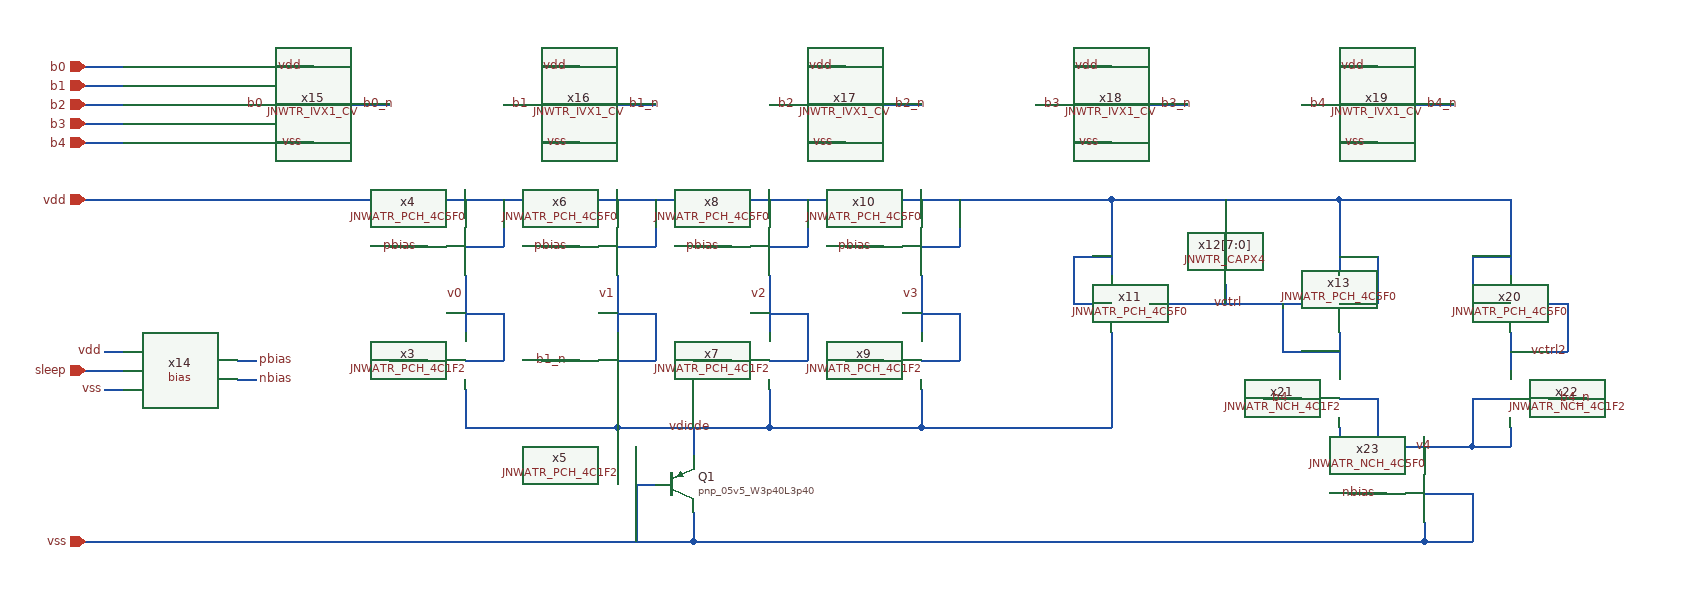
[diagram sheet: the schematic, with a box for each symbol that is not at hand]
v {xschem version=3.4.6 file_version=1.2}
G {}
K {}
V {}
S {}
E {}
N 830 540 830 570 {lab=vdiode}
N 510 350 550 350 {lab=pbias}
N 590 300 590 320 {lab=vdd}
N 590 380 590 440 {lab=v0}
N 590 500 590 540 {lab=vdiode}
N 510 470 550 470 {lab=b0_n}
N 590 350 630 350 {lab=vdd}
N 630 300 630 350 {lab=vdd}
N 590 470 630 470 {lab=v0}
N 630 420 630 470 {lab=v0}
N 590 420 630 420 {lab=v0}
N 590 540 750 540 {lab=vdiode}
N 670 350 710 350 {lab=pbias}
N 750 300 750 320 {lab=vdd}
N 750 380 750 440 {lab=v1}
N 750 500 750 540 {lab=vdiode}
N 670 470 710 470 {lab=b1_n}
N 750 350 790 350 {lab=vdd}
N 790 300 790 350 {lab=vdd}
N 750 470 790 470 {lab=v1}
N 790 420 790 470 {lab=v1}
N 750 420 790 420 {lab=v1}
N 750 540 910 540 {lab=vdiode}
N 830 350 870 350 {lab=pbias}
N 910 300 910 320 {lab=vdd}
N 910 380 910 440 {lab=v2}
N 910 500 910 540 {lab=vdiode}
N 830 470 870 470 {lab=b2_n}
N 910 350 950 350 {lab=vdd}
N 950 300 950 350 {lab=vdd}
N 910 470 950 470 {lab=v2}
N 950 420 950 470 {lab=v2}
N 910 420 950 420 {lab=v2}
N 910 540 1070 540 {lab=vdiode}
N 990 350 1030 350 {lab=pbias}
N 1070 300 1070 320 {lab=vdd}
N 1070 380 1070 440 {lab=v3}
N 1070 500 1070 540 {lab=vdiode}
N 990 470 1030 470 {lab=b3_n}
N 1070 350 1110 350 {lab=vdd}
N 1110 300 1110 350 {lab=vdd}
N 1070 470 1110 470 {lab=v3}
N 1110 420 1110 470 {lab=v3}
N 1070 420 1110 420 {lab=v3}
N 190 300 1270 300 {lab=vdd}
N 830 630 830 660 {lab=vss}
N 770 600 790 600 {lab=vss}
N 770 600 770 660 {lab=vss}
N 190 660 830 660 {lab=vss}
N 350 200 390 200 {lab=b0}
N 190 180 230 180 {lab=b1}
N 190 200 230 200 {lab=b2}
N 190 220 230 220 {lab=b3}
N 190 240 230 240 {lab=b4}
N 390 160 430 160 {lab=vdd}
N 390 240 430 240 {lab=vss}
N 470 200 510 200 {lab=b0_n}
N 630 200 670 200 {lab=b1}
N 670 160 710 160 {lab=vdd}
N 670 240 710 240 {lab=vss}
N 750 200 790 200 {lab=b1_n}
N 910 200 950 200 {lab=b2}
N 950 160 990 160 {lab=vdd}
N 950 240 990 240 {lab=vss}
N 1030 200 1070 200 {lab=b2_n}
N 1190 200 1230 200 {lab=b3}
N 1230 160 1270 160 {lab=vdd}
N 1230 240 1270 240 {lab=vss}
N 1310 200 1350 200 {lab=b3_n}
N 1470 200 1510 200 {lab=b4}
N 1510 160 1550 160 {lab=vdd}
N 1510 240 1550 240 {lab=vss}
N 1590 200 1630 200 {lab=b4_n}
N 190 160 230 160 {lab=b0}
N 190 480 230 480 {lab=sleep}
N 350 490 370 490 {lab=nbias}
N 350 470 370 470 {lab=pbias}
N 210 500 230 500 {lab=nbias}
N 210 460 230 460 {lab=vdd}
N 1310 410 1470 410 {lab=vctrl}
N 1270 300 1270 380 {lab=vdd}
N 1070 540 1270 540 {lab=vdiode}
N 830 660 1600 660 {lab=vss}
N 1390 390 1390 410 {lab=vctrl}
N 1390 300 1390 320 {lab=vdd}
N 1270 300 1510 300 {lab=vdd}
N 1510 300 1510 380 {lab=vdd}
N 1510 410 1550 410 {lab=vdd}
N 1550 360 1550 410 {lab=vdd}
N 1510 360 1550 360 {lab=vdd}
N 1450 410 1450 460 {lab=vctrl}
N 1450 460 1510 460 {lab=vctrl}
N 1510 440 1510 480 {lab=vctrl}
N 1730 410 1750 410 {lab=vctrl2}
N 1690 300 1690 380 {lab=vdd}
N 1650 410 1690 410 {lab=vdd}
N 1650 360 1650 410 {lab=vdd}
N 1750 410 1750 460 {lab=vctrl2}
N 1690 460 1750 460 {lab=vctrl2}
N 1690 440 1690 480 {lab=vctrl2}
N 1510 300 1690 300 {lab=vdd}
N 1650 360 1690 360 {lab=vdd}
N 1270 440 1270 540 {lab=vdiode}
N 1650 510 1690 510 {lab=v4}
N 1650 510 1650 560 {lab=v4}
N 1650 560 1690 560 {lab=v4}
N 1510 510 1550 510 {lab=v4}
N 1550 510 1550 560 {lab=v4}
N 1510 560 1550 560 {lab=v4}
N 1510 540 1510 560 {lab=v4}
N 1690 540 1690 560 {lab=v4}
N 1430 510 1470 510 {lab=b4}
N 1730 510 1770 510 {lab=b4_n}
N 1550 560 1650 560 {lab=v4}
N 1600 560 1600 580 {lab=v4}
N 1650 610 1650 660 {lab=vss}
N 1230 410 1270 410 {lab=vdd}
N 1230 360 1230 410 {lab=vdd}
N 1230 360 1270 360 {lab=vdd}
N 1600 640 1600 660 {lab=vss}
N 1600 610 1650 610 {lab=vss}
N 1600 660 1650 660 {lab=vss}
N 1520 610 1560 610 {lab=nbias}
C {JNW_ATR_SKY130A/JNWATR_PCH_4C5F0.sym} 550 350 0 0 {name=x4 }
C {JNW_ATR_SKY130A/JNWATR_PCH_4C5F0.sym} 710 350 0 0 {name=x6 }
C {JNW_ATR_SKY130A/JNWATR_PCH_4C5F0.sym} 870 350 0 0 {name=x8 }
C {JNW_ATR_SKY130A/JNWATR_PCH_4C5F0.sym} 1030 350 0 0 {name=x10 }
C {devices/lab_wire.sym} 1020 470 0 0 {name=p3 sig_type=std_logic lab=b3_n
}
C {devices/lab_wire.sym} 860 470 0 0 {name=p4 sig_type=std_logic lab=b2_n
}
C {devices/lab_wire.sym} 700 470 0 0 {name=p5 sig_type=std_logic lab=b1_n
}
C {devices/lab_wire.sym} 540 470 0 0 {name=p6 sig_type=std_logic lab=b0_n
}
C {devices/ipin.sym} 190 300 0 0 {name=p14 lab=vdd}
C {sky130_fd_pr/pnp_05v5.sym} 810 600 0 0 {name=Q1
model=pnp_05v5_W3p40L3p40
m=1
spiceprefix=X
}
C {devices/ipin.sym} 190 660 0 0 {name=p15 lab=vss}
C {devices/ipin.sym} 190 180 0 0 {name=p17 lab=b1}
C {devices/ipin.sym} 190 200 0 0 {name=p18 lab=b2}
C {devices/ipin.sym} 190 220 0 0 {name=p19 lab=b3}
C {devices/ipin.sym} 190 240 0 0 {name=p20 lab=b4}
C {JNW_TR_SKY130A/JNWTR_IVX1_CV.sym} 390 200 0 0 {name=x15 }
C {devices/lab_wire.sym} 420 240 2 1 {name=p23 sig_type=std_logic lab=vss}
C {devices/lab_wire.sym} 420 160 0 0 {name=p24 sig_type=std_logic lab=vdd}
C {JNW_TR_SKY130A/JNWTR_IVX1_CV.sym} 670 200 0 0 {name=x16 }
C {devices/lab_wire.sym} 700 240 2 1 {name=p26 sig_type=std_logic lab=vss}
C {devices/lab_wire.sym} 700 160 0 0 {name=p27 sig_type=std_logic lab=vdd}
C {JNW_TR_SKY130A/JNWTR_IVX1_CV.sym} 950 200 0 0 {name=x17 }
C {devices/lab_wire.sym} 980 240 2 1 {name=p30 sig_type=std_logic lab=vss}
C {devices/lab_wire.sym} 980 160 0 0 {name=p31 sig_type=std_logic lab=vdd}
C {JNW_TR_SKY130A/JNWTR_IVX1_CV.sym} 1230 200 0 0 {name=x18 }
C {devices/lab_wire.sym} 1260 240 2 1 {name=p34 sig_type=std_logic lab=vss}
C {devices/lab_wire.sym} 1260 160 0 0 {name=p35 sig_type=std_logic lab=vdd}
C {JNW_TR_SKY130A/JNWTR_IVX1_CV.sym} 1510 200 0 0 {name=x19 }
C {devices/lab_wire.sym} 1540 240 2 1 {name=p38 sig_type=std_logic lab=vss}
C {devices/lab_wire.sym} 1540 160 0 0 {name=p39 sig_type=std_logic lab=vdd}
C {devices/lab_wire.sym} 380 200 0 0 {name=p16 sig_type=std_logic lab=b0}
C {devices/lab_wire.sym} 1220 200 0 0 {name=p25 sig_type=std_logic lab=b3}
C {devices/lab_wire.sym} 660 200 0 0 {name=p28 sig_type=std_logic lab=b1}
C {devices/lab_wire.sym} 1500 200 0 0 {name=p29 sig_type=std_logic lab=b4}
C {devices/lab_wire.sym} 940 200 0 0 {name=p32 sig_type=std_logic lab=b2}
C {devices/ipin.sym} 190 160 0 0 {name=p7 lab=b0}
C {devices/lab_wire.sym} 1320 200 0 1 {name=p36 sig_type=std_logic lab=b3_n}
C {devices/lab_wire.sym} 480 200 0 1 {name=p37 sig_type=std_logic lab=b0_n}
C {devices/lab_wire.sym} 760 200 0 1 {name=p40 sig_type=std_logic lab=b1_n}
C {devices/lab_wire.sym} 1600 200 0 1 {name=p41 sig_type=std_logic lab=b4_n}
C {devices/lab_wire.sym} 1040 200 0 1 {name=p45 sig_type=std_logic lab=b2_n}
C {devices/lab_wire.sym} 700 350 0 0 {name=p9 sig_type=std_logic lab=pbias
}
C {devices/lab_wire.sym} 860 350 0 0 {name=p8 sig_type=std_logic lab=pbias
}
C {devices/lab_wire.sym} 1020 350 0 0 {name=p10 sig_type=std_logic lab=pbias
}
C {devices/lab_wire.sym} 540 350 0 0 {name=p12 sig_type=std_logic lab=pbias
}
C {LELO_TORD_SKY130A/bias.sym} 290 480 0 0 {name=x14}
C {devices/ipin.sym} 190 480 0 0 {name=p33 lab=sleep}
C {devices/lab_wire.sym} 370 470 0 1 {name=p13 sig_type=std_logic lab=pbias
}
C {devices/lab_wire.sym} 370 490 2 0 {name=p21 sig_type=std_logic lab=nbias
}
C {devices/lab_wire.sym} 850 540 0 0 {name=p22 sig_type=std_logic lab=vdiode
}
C {JNW_ATR_SKY130A/JNWATR_PCH_4C5F0.sym} 1310 410 0 1 {name=x11 }
C {JNW_ATR_SKY130A/JNWATR_PCH_4C1F2.sym} 550 470 0 0 {name=x3 }
C {JNW_ATR_SKY130A/JNWATR_PCH_4C1F2.sym} 710 470 0 0 {name=x5 }
C {JNW_ATR_SKY130A/JNWATR_PCH_4C1F2.sym} 870 470 0 0 {name=x7 }
C {JNW_ATR_SKY130A/JNWATR_PCH_4C1F2.sym} 1030 470 0 0 {name=x9 }
C {JNW_TR_SKY130A/JNWTR_CAPX4.sym} 1390 380 0 0 {name=x12[7:0]}
C {JNW_ATR_SKY130A/JNWATR_PCH_4C5F0.sym} 1470 410 0 0 {name=x13 }
C {JNW_ATR_SKY130A/JNWATR_PCH_4C5F0.sym} 1730 410 0 1 {name=x20 }
C {JNW_ATR_SKY130A/JNWATR_NCH_4C1F2.sym} 1470 510 0 0 {name=x21 }
C {JNW_ATR_SKY130A/JNWATR_NCH_4C1F2.sym} 1730 510 0 1 {name=x22 }
C {devices/lab_wire.sym} 1740 510 0 1 {name=p1 sig_type=std_logic lab=b4_n}
C {devices/lab_wire.sym} 1460 510 0 0 {name=p2 sig_type=std_logic lab=b4}
C {JNW_ATR_SKY130A/JNWATR_NCH_4C5F0.sym} 1560 610 0 0 {name=x23 }
C {devices/lab_wire.sym} 1550 610 2 1 {name=p11 sig_type=std_logic lab=nbias
}
C {devices/lab_wire.sym} 1410 410 2 1 {name=p42 sig_type=std_logic lab=vctrl}
C {devices/lab_wire.sym} 1710 460 2 0 {name=p43 sig_type=std_logic lab=vctrl2}
C {devices/lab_wire.sym} 1610 560 0 0 {name=p44 sig_type=std_logic lab=v4}
C {devices/lab_wire.sym} 1070 400 2 1 {name=p46 sig_type=std_logic lab=v3}
C {devices/lab_wire.sym} 910 400 2 1 {name=p47 sig_type=std_logic lab=v2}
C {devices/lab_wire.sym} 750 400 2 1 {name=p48 sig_type=std_logic lab=v1}
C {devices/lab_wire.sym} 590 400 2 1 {name=p49 sig_type=std_logic lab=v0
}
C {devices/lab_wire.sym} 210 500 2 1 {name=p50 sig_type=std_logic lab=vss
}
C {devices/lab_wire.sym} 210 460 0 0 {name=p51 sig_type=std_logic lab=vdd
}
